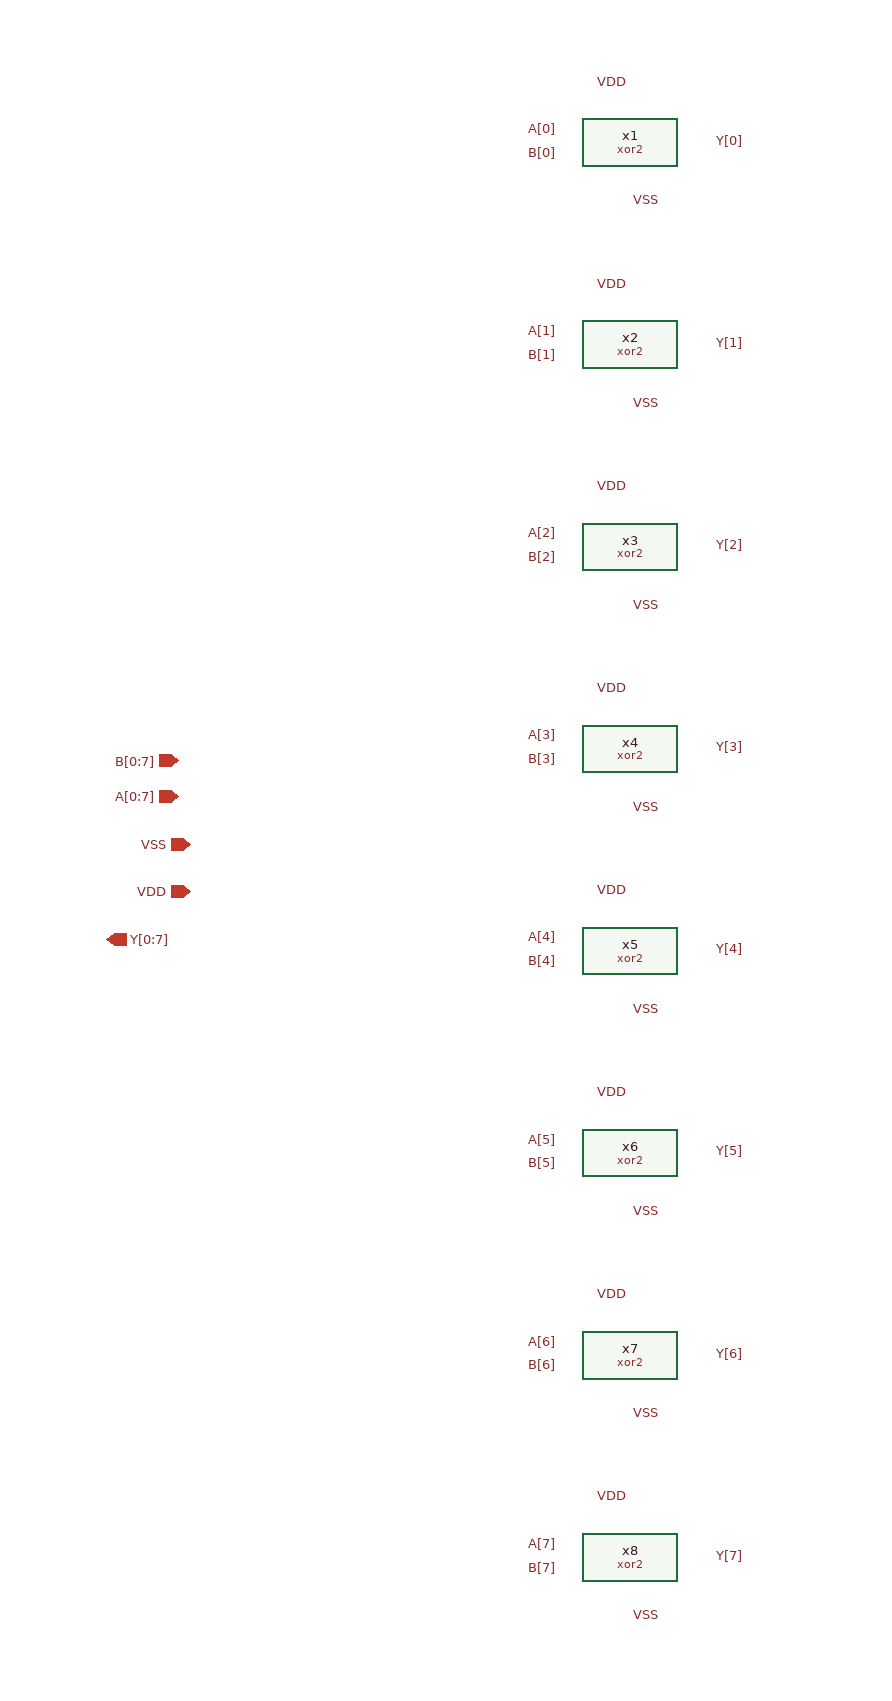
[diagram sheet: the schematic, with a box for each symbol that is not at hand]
v {xschem version=3.1.0 file_version=1.2 }
G {}
K {}
V {}
S {}
E {}
C {devices/ipin.sym} -370 320 0 0 {name=p3 lab=A[0:7]}
C {devices/opin.sym} -430 440 0 0 {name=p9 lab=Y[0:7]}
C {devices/iopin.sym} -360 360 2 0 {name=p6 lab=VSS}
C {devices/iopin.sym} -360 400 2 0 {name=p7 lab=VDD}
C {devices/lab_pin.sym} 10 -280 1 0 {name=l3 sig_type=std_logic lab=VDD}
C {devices/ipin.sym} -370 290 0 0 {name=p1 lab=B[0:7]}
C {devices/lab_pin.sym} -50 -240 0 0 {name=l12 sig_type=std_logic lab=A[0]}
C {devices/lab_pin.sym} -50 -220 0 0 {name=l18 sig_type=std_logic lab=B[0]}
C {devices/lab_pin.sym} 10 -180 2 0 {name=l25 sig_type=std_logic lab=VSS}
C {devices/lab_pin.sym} 80 -230 2 0 {name=l26 sig_type=std_logic lab=Y[0]}
C {xor2.sym} 10 -230 0 0 {name=x1}
C {devices/lab_pin.sym} 10 -110 1 0 {name=l1 sig_type=std_logic lab=VDD}
C {devices/lab_pin.sym} -50 -70 0 0 {name=l2 sig_type=std_logic lab=A[1]}
C {devices/lab_pin.sym} -50 -50 0 0 {name=l4 sig_type=std_logic lab=B[1]}
C {devices/lab_pin.sym} 10 -10 2 0 {name=l5 sig_type=std_logic lab=VSS}
C {devices/lab_pin.sym} 80 -60 2 0 {name=l6 sig_type=std_logic lab=Y[1]}
C {xor2.sym} 10 -60 0 0 {name=x2}
C {devices/lab_pin.sym} 10 60 1 0 {name=l7 sig_type=std_logic lab=VDD}
C {devices/lab_pin.sym} -50 100 0 0 {name=l8 sig_type=std_logic lab=A[2]}
C {devices/lab_pin.sym} -50 120 0 0 {name=l9 sig_type=std_logic lab=B[2]}
C {devices/lab_pin.sym} 10 160 2 0 {name=l10 sig_type=std_logic lab=VSS}
C {devices/lab_pin.sym} 80 110 2 0 {name=l11 sig_type=std_logic lab=Y[2]}
C {xor2.sym} 10 110 0 0 {name=x3}
C {devices/lab_pin.sym} 10 230 1 0 {name=l13 sig_type=std_logic lab=VDD}
C {devices/lab_pin.sym} -50 270 0 0 {name=l14 sig_type=std_logic lab=A[3]}
C {devices/lab_pin.sym} -50 290 0 0 {name=l15 sig_type=std_logic lab=B[3]}
C {devices/lab_pin.sym} 10 330 2 0 {name=l16 sig_type=std_logic lab=VSS}
C {devices/lab_pin.sym} 80 280 2 0 {name=l17 sig_type=std_logic lab=Y[3]}
C {xor2.sym} 10 280 0 0 {name=x4}
C {devices/lab_pin.sym} 10 400 1 0 {name=l19 sig_type=std_logic lab=VDD}
C {devices/lab_pin.sym} -50 440 0 0 {name=l20 sig_type=std_logic lab=A[4]}
C {devices/lab_pin.sym} -50 460 0 0 {name=l21 sig_type=std_logic lab=B[4]}
C {devices/lab_pin.sym} 10 500 2 0 {name=l22 sig_type=std_logic lab=VSS}
C {devices/lab_pin.sym} 80 450 2 0 {name=l23 sig_type=std_logic lab=Y[4]}
C {xor2.sym} 10 450 0 0 {name=x5}
C {devices/lab_pin.sym} 10 570 1 0 {name=l24 sig_type=std_logic lab=VDD}
C {devices/lab_pin.sym} -50 610 0 0 {name=l27 sig_type=std_logic lab=A[5]}
C {devices/lab_pin.sym} -50 630 0 0 {name=l28 sig_type=std_logic lab=B[5]}
C {devices/lab_pin.sym} 10 670 2 0 {name=l29 sig_type=std_logic lab=VSS}
C {devices/lab_pin.sym} 80 620 2 0 {name=l30 sig_type=std_logic lab=Y[5]}
C {xor2.sym} 10 620 0 0 {name=x6}
C {devices/lab_pin.sym} 10 740 1 0 {name=l31 sig_type=std_logic lab=VDD}
C {devices/lab_pin.sym} -50 780 0 0 {name=l32 sig_type=std_logic lab=A[6]}
C {devices/lab_pin.sym} -50 800 0 0 {name=l33 sig_type=std_logic lab=B[6]}
C {devices/lab_pin.sym} 10 840 2 0 {name=l34 sig_type=std_logic lab=VSS}
C {devices/lab_pin.sym} 80 790 2 0 {name=l35 sig_type=std_logic lab=Y[6]}
C {xor2.sym} 10 790 0 0 {name=x7}
C {devices/lab_pin.sym} 10 910 1 0 {name=l36 sig_type=std_logic lab=VDD}
C {devices/lab_pin.sym} -50 950 0 0 {name=l37 sig_type=std_logic lab=A[7]}
C {devices/lab_pin.sym} -50 970 0 0 {name=l38 sig_type=std_logic lab=B[7]}
C {devices/lab_pin.sym} 10 1010 2 0 {name=l39 sig_type=std_logic lab=VSS}
C {devices/lab_pin.sym} 80 960 2 0 {name=l40 sig_type=std_logic lab=Y[7]}
C {xor2.sym} 10 960 0 0 {name=x8}
